VERSION 5.7 ;
  NOWIREEXTENSIONATPIN ON ;
  DIVIDERCHAR "/" ;
  BUSBITCHARS "[]" ;
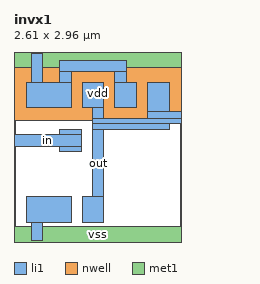
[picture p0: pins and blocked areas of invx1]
MACRO invx1
  CLASS BLOCK ;
  FOREIGN invx1 ;
  ORIGIN 0.900 0.260 ;
  SIZE 2.610 BY 2.960 ;
  PIN in
    ANTENNAGATEAREA 0.252000 ;
    PORT
      LAYER li1 ;
        RECT -0.190 1.410 0.150 1.490 ;
        RECT -0.900 1.230 0.150 1.410 ;
        RECT -0.190 1.150 0.150 1.230 ;
    END
  END in
  PIN out
    ANTENNADIFFAREA 0.453600 ;
    PORT
      LAYER li1 ;
        RECT 0.160 1.830 0.500 2.230 ;
        RECT 0.320 1.660 0.500 1.830 ;
        RECT 1.180 1.770 1.520 2.230 ;
        RECT 1.180 1.660 1.710 1.770 ;
        RECT 0.320 1.590 1.710 1.660 ;
        RECT 0.320 1.490 1.520 1.590 ;
        RECT 0.320 0.450 0.500 1.490 ;
        RECT 0.160 0.050 0.500 0.450 ;
    END
  END out
  PIN vdd
    ANTENNADIFFAREA 0.453600 ;
    PORT
      LAYER nwell ;
        RECT -0.900 1.640 1.710 2.480 ;
      LAYER li1 ;
        RECT -0.630 2.230 -0.450 2.670 ;
        RECT -0.190 2.400 0.850 2.570 ;
        RECT -0.190 2.230 -0.010 2.400 ;
        RECT -0.710 1.830 -0.010 2.230 ;
        RECT 0.670 2.230 0.850 2.400 ;
        RECT 0.670 1.830 1.010 2.230 ;
      LAYER met1 ;
        RECT -0.900 2.460 1.710 2.700 ;
    END
  END vdd
  PIN vss
    ANTENNADIFFAREA 0.302400 ;
    PORT
      LAYER li1 ;
        RECT -0.710 0.050 -0.010 0.450 ;
        RECT -0.630 -0.230 -0.450 0.050 ;
      LAYER met1 ;
        RECT -0.900 -0.260 1.710 -0.020 ;
    END
  END vss
END invx1
END LIBRARY

